One B-rep face of a CAD part: STEP entity #10.
In plain terms, the planar face has unit normal (0, 1, 0).
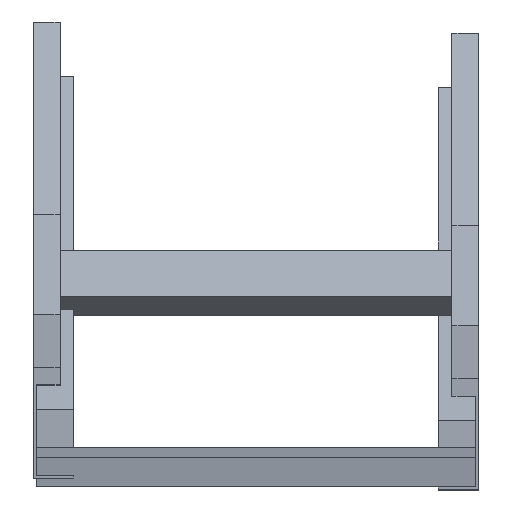
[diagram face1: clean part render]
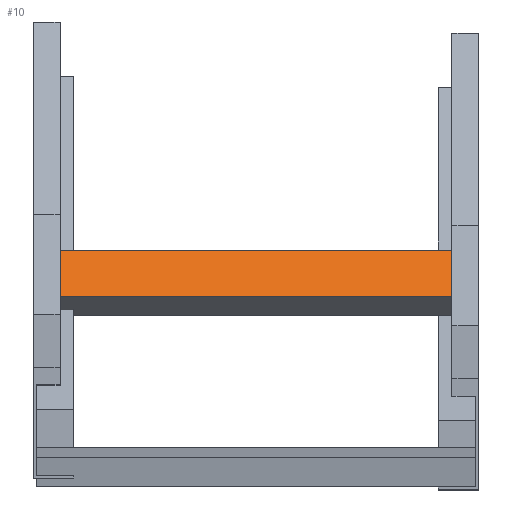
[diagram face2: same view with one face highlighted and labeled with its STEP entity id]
Its self-contained STEP definition (entity closure, numbers rounded to 3 decimals):
#10 = ADVANCED_FACE ( 'NONE', ( #261 ), #954, .F. ) ;
#129 = LINE ( 'NONE', #1531, #1295 ) ;
#184 = CARTESIAN_POINT ( 'NONE',  ( 148., 20., 20.25 ) ) ;
#216 = CARTESIAN_POINT ( 'NONE',  ( 148., 20., 20.25 ) ) ;
#261 = FACE_OUTER_BOUND ( 'NONE', #948, .T. ) ;
#307 = CARTESIAN_POINT ( 'NONE',  ( 148., 20., 20.25 ) ) ;
#329 = VECTOR ( 'NONE', #993, 1000. ) ;
#333 = CARTESIAN_POINT ( 'NONE',  ( -148., 20., 20.25 ) ) ;
#340 = VERTEX_POINT ( 'NONE', #816 ) ;
#354 = DIRECTION ( 'NONE',  ( -1., 0., 0. ) ) ;
#445 = LINE ( 'NONE', #333, #1157 ) ;
#488 = DIRECTION ( 'NONE',  ( -1., 0., 0. ) ) ;
#569 = DIRECTION ( 'NONE',  ( 0., -1., 0. ) ) ;
#576 = ORIENTED_EDGE ( 'NONE', *, *, #1398, .T. ) ;
#689 = CARTESIAN_POINT ( 'NONE',  ( -148., 20., -20.25 ) ) ;
#702 = VERTEX_POINT ( 'NONE', #1477 ) ;
#816 = CARTESIAN_POINT ( 'NONE',  ( 148., 20., -20.25 ) ) ;
#864 = ORIENTED_EDGE ( 'NONE', *, *, #981, .F. ) ;
#889 = AXIS2_PLACEMENT_3D ( 'NONE', #307, #569, #1434 ) ;
#948 = EDGE_LOOP ( 'NONE', ( #576, #1582, #864, #1125 ) ) ;
#954 = PLANE ( 'NONE',  #889 ) ;
#964 = VECTOR ( 'NONE', #488, 1000. ) ;
#981 = EDGE_CURVE ( 'NONE', #340, #1225, #1647, .T. ) ;
#987 = CARTESIAN_POINT ( 'NONE',  ( 148., 20., 20.25 ) ) ;
#993 = DIRECTION ( 'NONE',  ( 0., 0., 1. ) ) ;
#1125 = ORIENTED_EDGE ( 'NONE', *, *, #1478, .T. ) ;
#1157 = VECTOR ( 'NONE', #1256, 1000. ) ;
#1167 = VERTEX_POINT ( 'NONE', #689 ) ;
#1225 = VERTEX_POINT ( 'NONE', #184 ) ;
#1256 = DIRECTION ( 'NONE',  ( 0., 0., 1. ) ) ;
#1295 = VECTOR ( 'NONE', #354, 1000. ) ;
#1398 = EDGE_CURVE ( 'NONE', #1167, #702, #445, .T. ) ;
#1434 = DIRECTION ( 'NONE',  ( 0., 0., -1. ) ) ;
#1477 = CARTESIAN_POINT ( 'NONE',  ( -148., 20., 20.25 ) ) ;
#1478 = EDGE_CURVE ( 'NONE', #340, #1167, #129, .T. ) ;
#1479 = LINE ( 'NONE', #987, #964 ) ;
#1531 = CARTESIAN_POINT ( 'NONE',  ( 148., 20., -20.25 ) ) ;
#1582 = ORIENTED_EDGE ( 'NONE', *, *, #1676, .F. ) ;
#1647 = LINE ( 'NONE', #216, #329 ) ;
#1676 = EDGE_CURVE ( 'NONE', #1225, #702, #1479, .T. ) ;
